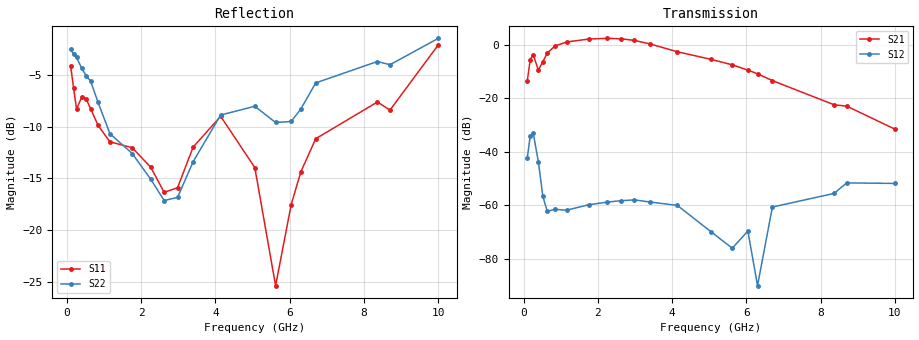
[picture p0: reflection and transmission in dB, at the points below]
! Integrated Device Technology
! Corporate Headquarters
! 6024 Silver Creek Valley Road
! San Jose, CA 95138  USA
! Phone:  1-408-284-8200
! Toll Free:  1-800-223-1366
! Webpage:  http://www.idt.com/
! Timing and RF Division
! 515 Groton Road, Suite 102
! Westford, MA 01886-6024
! Device:  F1456
! Description: 6-bit 0.5 dB Transmit Variable Gain Amplifier
! Frequency:  2100.0 -  2950.00 MHz
! Package:  6x6 mm Thin QFN Plastic Package: 28 pin
! State:  59
! Atten State:  29.5 dB
! Voltage:  +5.00 Volts
! Current:  216.921 mA
! Data:  The device was measured on a the F1455 evaluation board which has
!  individual transmission lines to the RF pins.  Data was collected
!  using a calibrated network analyzer.  The evaluation board was
!  de-embedded using a TRL calibration technique.
!  The reference plane is the edge of the package pin.
!  Pin  1 = CSb
!  Pin  2 = DATA
!  Pin  3 = CLK
!  Pin  4 = RSET
!  Pin  5 = GND
!  Pin  6 = RFIN  = Port 1
!  Pin  7 = GND
!  Pin  8 = NC
!  Pin  9 = NC
!  Pin 10 = NC
!  Pin 11 = NC
!  Pin 12 = NC
!  Pin 13 = NC
!  Pin 14 = /STBY
!  Pin 15 = GND
!  Pin 16 = RFOUT  = Port 2
!  Pin 17 = GND
!  Pin 18 = NC
!  Pin 19 = NC
!  Pin 20 = NC
!  Pin 21 = GND
!  Pin 22 = NC
!  Pin 23 = GND
!  Pin 24 = NC
!  Pin 25 = NC
!  Pin 26 = NC
!  Pin 27 = GND
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# GHz S dB R 50
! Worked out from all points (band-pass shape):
!   496 points, 100 MHz to 10 GHz, reference 50 ohm
!   highest |S21| = 2.44 dB at 2.26 GHz (marker M1); lowest = -31.5 dB at 10 GHz (marker M2)
!   |S21| within 3 dB of the highest: 827.3 MHz to 3.641 GHz (2.814 GHz wide, 126 % of centre)
!   lowest |S11| = -25.4 dB at 5.62 GHz (marker M3), VSWR 1.11, Z = 52 + j5.11 ohm
!   |S11| at or under -10 dB: 857.4 MHz to 3.714 GHz (2.857 GHz wide, 125 % of centre); 4.605 GHz to 6.902 GHz (2.297 GHz wide, 39.9 % of centre); 6.983 GHz to 7.061 GHz (77.84 MHz wide, 1.11 % of centre)
!   |S22| runs from -17.4 to -1.5 dB; largest |S21 - S12| = 1.3
!   S11 on the Smith chart (normalised r, x): 100 MHz: 2.37, -2.04; 640 MHz: 1.03, -0.85; 2.98 GHz: 0.77, +0.17; 6.04 GHz: 1.29, +0.10; 8.7 GHz: 0.90, +0.78; 10 GHz: 4.19, +4.11
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0.1  -4.10 -24.9  -13.60 -150.7  -42.28 50.5  -2.51 140.7
0.18  -6.24 -40.1  -5.47 158.8  -34.16 -2.4  -2.98 109.7
0.26  -8.29 -28.5  -3.62 60.1  -32.88 -100.6  -3.30 88.8
0.4  -7.15 -33.9  -9.46 -92.2  -43.74 150.2  -4.36 44.4
0.52  -7.33 -50.8  -6.27 164.5  -56.66 115.5  -5.07 21.0
0.64  -8.27 -65.5  -3.06 111.8  -62.25 139.4  -5.61 -6.2
0.84  -9.88 -86.1  -0.46 55.2  -61.48 117.8  -7.65 -48.6
1.16  -11.47 -112.0  1.08 -3.1  -61.79 87.3  -10.69 -94.7
1.76  -12.04 -139.0  2.19 -82.4  -59.74 56.0  -12.60 -139.6
2.26  -13.94 -155.2  2.44 -138.6  -58.78 38.4  -15.10 -159.1
2.62  -16.36 -180.0  2.29 -178.0  -58.25 25.9  -17.15 -176.6
2.98  -15.91 138.2  1.69 143.2  -57.95 10.4  -16.85 157.6
3.4  -11.98 113.4  0.38 100.5  -58.72 -7.1  -13.39 137.6
4.14  -9.00 113.1  -2.56 36.8  -60.00 -40.2  -8.88 132.1
5.06  -13.96 122.8  -5.45 -36.0  -69.98 -79.2  -8.03 139.1
5.62  -25.39 65.9  -7.45 -84.0  -76.01 163.9  -9.60 124.7
6.04  -17.54 16.3  -9.42 -122.6  -69.59 136.5  -9.50 95.2
6.3  -14.37 22.6  -10.81 -146.1  -90.02 -141.8  -8.29 78.7
6.7  -11.17 40.7  -13.35 177.3  -60.62 142.8  -5.77 65.3
8.36  -7.62 88.6  -22.38 64.2  -55.53 56.2  -3.70 62.3
8.7  -8.40 74.9  -22.89 37.6  -51.59 67.1  -4.01 51.1
10  -2.09 13.8  -31.51 -69.1  -51.79 -26.5  -1.46 -2.6
